VERSION 5.8 ;

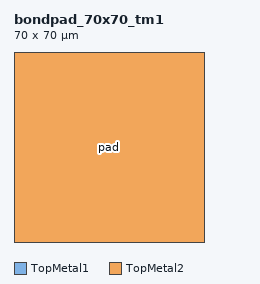
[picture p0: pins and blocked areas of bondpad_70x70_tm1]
MACRO bondpad_70x70_tm1
  CLASS COVER ;
  ORIGIN 0 0 ;
  FOREIGN bondpad_70x70_tm1 0 0 ;
  SIZE 70.0 BY 70.0 ;
  SYMMETRY X Y R90 ;
  SITE sg13g2_ioSite ;
  PIN pad
    DIRECTION INOUT ;
    USE SIGNAL ;
    PORT
      LAYER TopMetal1 ;
        RECT 0 0 70.0 70.0 ;
      LAYER TopMetal2 ;
        RECT 0 0 70.0 70.0 ;
    END
  END pad
  OBS
    LAYER TopMetal1 ;
      RECT 0 0 70.0 70.0 ;
    LAYER TopMetal2 ;
      RECT 0 0 70.0 70.0 ;
  END
END bondpad_70x70_tm1
